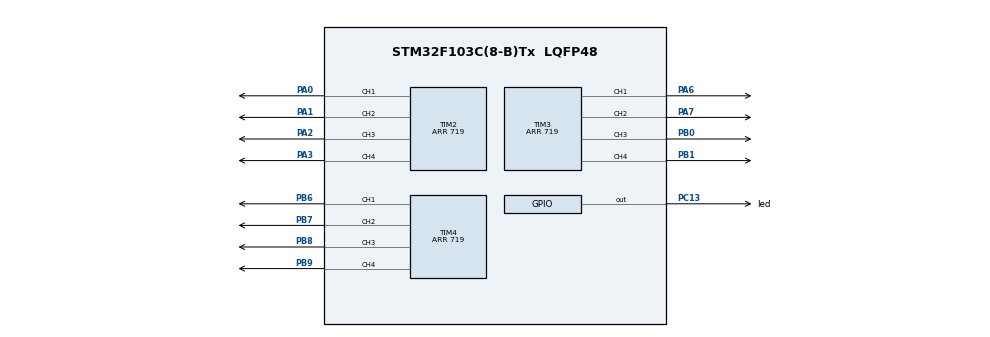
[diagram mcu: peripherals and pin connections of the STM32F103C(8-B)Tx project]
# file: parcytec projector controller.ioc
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Mcu.Family=STM32F1
Mcu.Name=STM32F103C(8-B)Tx
Mcu.Package=LQFP48
NVIC.PriorityGroup=NVIC_PRIORITYGROUP_4
PA0-WKUP.Signal=S_TIM2_CH1_ETR
PA1.Signal=S_TIM2_CH2
PA13.Mode=Serial_Wire
PA13.Signal=SYS_JTMS-SWDIO
PA14.Mode=Serial_Wire
PA14.Signal=SYS_JTCK-SWCLK
PA2.Signal=S_TIM2_CH3
PA3.Signal=S_TIM2_CH4
PA6.Signal=S_TIM3_CH1
PA7.Signal=S_TIM3_CH2
PB0.Signal=S_TIM3_CH3
PB1.Signal=S_TIM3_CH4
PB6.Signal=S_TIM4_CH1
PB7.Signal=S_TIM4_CH2
PB8.Signal=S_TIM4_CH3
PB9.Signal=S_TIM4_CH4
PC13-TAMPER-RTC.GPIO_Label=led
PC13-TAMPER-RTC.Signal=GPIO_Output
PD0-OSC_IN.Mode=HSE-External-Oscillator
PD0-OSC_IN.Signal=RCC_OSC_IN
PD1-OSC_OUT.Mode=HSE-External-Oscillator
PD1-OSC_OUT.Signal=RCC_OSC_OUT
ProjectManager.HeapSize=0x200
ProjectManager.StackSize=0x400
ProjectManager.TargetToolchain=MDK-ARM V5.32
RCC.APB1Freq_Value=8000000
RCC.APB2Freq_Value=8000000
SH.S_TIM2_CH1_ETR.0=TIM2_CH1,PWM Generation1 CH1
SH.S_TIM2_CH2.0=TIM2_CH2,PWM Generation2 CH2
SH.S_TIM2_CH3.0=TIM2_CH3,PWM Generation3 CH3
SH.S_TIM2_CH4.0=TIM2_CH4,PWM Generation4 CH4
SH.S_TIM3_CH1.0=TIM3_CH1,PWM Generation1 CH1
SH.S_TIM3_CH2.0=TIM3_CH2,PWM Generation2 CH2
SH.S_TIM3_CH3.0=TIM3_CH3,PWM Generation3 CH3
SH.S_TIM3_CH4.0=TIM3_CH4,PWM Generation4 CH4
SH.S_TIM4_CH1.0=TIM4_CH1,PWM Generation1 CH1
SH.S_TIM4_CH2.0=TIM4_CH2,PWM Generation2 CH2
SH.S_TIM4_CH3.0=TIM4_CH3,PWM Generation3 CH3
SH.S_TIM4_CH4.0=TIM4_CH4,PWM Generation4 CH4
TIM2.Channel-PWM\ Generation1\ CH1=TIM_CHANNEL_1
TIM2.Channel-PWM\ Generation2\ CH2=TIM_CHANNEL_2
TIM2.Channel-PWM\ Generation3\ CH3=TIM_CHANNEL_3
TIM2.Channel-PWM\ Generation4\ CH4=TIM_CHANNEL_4
TIM2.Period=719
TIM3.Channel-PWM\ Generation1\ CH1=TIM_CHANNEL_1
TIM3.Channel-PWM\ Generation2\ CH2=TIM_CHANNEL_2
TIM3.Channel-PWM\ Generation3\ CH3=TIM_CHANNEL_3
TIM3.Channel-PWM\ Generation4\ CH4=TIM_CHANNEL_4
TIM3.Period=719
TIM4.Channel-PWM\ Generation1\ CH1=TIM_CHANNEL_1
TIM4.Channel-PWM\ Generation2\ CH2=TIM_CHANNEL_2
TIM4.Channel-PWM\ Generation3\ CH3=TIM_CHANNEL_3
TIM4.Channel-PWM\ Generation4\ CH4=TIM_CHANNEL_4
TIM4.Period=719
board=custom

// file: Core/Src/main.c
#include "main.h"

int period_value=72000/100;

TIM_HandleTypeDef htim2;
TIM_HandleTypeDef htim3;
TIM_HandleTypeDef htim4;

void SystemClock_Config(void);
static void MX_GPIO_Init(void);
static void MX_TIM2_Init(void);
static void MX_TIM3_Init(void);
static void MX_TIM4_Init(void);

int main(void)
{
  HAL_Init();
  SystemClock_Config();

  MX_GPIO_Init();
  MX_TIM2_Init();
  MX_TIM3_Init();
  MX_TIM4_Init();

	/////////////////declare variables///////////////////

	int delay_value=1000/10;   // 1000/freq of pwm for led  PC13

///////////////configuration of TIM1/////////////////
	///////0.6 A without any LED//////////

	int compare_value1=period_value*0.45; // defining the duty cycle of pwm/////////////  1  ///////  D C =0.4    1A /// D C =0.38 0.9A   0.3+0.9=1.2 //// 0.5
	int compare_value2=period_value*0.2; // defining the duty cycle of pwm//////////////  2  ///////  D C =0.15   1A /// D C =0.1 0.9A    1.2+0.9=2.1/////0.2
	int compare_value3=period_value*0.3; // defining the duty cycle of pwm/////////////  3  ///////  D C =0.25   1A /// D C =0.22 0.9A   2.1+0.9=3/////0.3
	int compare_value4=period_value*0.2; // defining the duty cycle of pwm/////////////  4  ///////  D C =0.15   1A /// D C =0.11 0.9A		3+0.9=3.9////0.2
	int compare_value5=period_value*0.25; // defining the duty cycle of pwm/////////////  5  ///////  D C =0.15   1A /// D C =0.13 0.9A		3.9+0.9=4.8///0.25
	int compare_value6=period_value*0.45; // defining the duty cycle of pwm/////////////  6  ///////  D C =---    1A /// D C =0.45 0.9A		4.8+0.9=5.7////0.55
	int compare_value7=period_value*0.45; // defining the duty cycle of pwm //
	int compare_value8=period_value*0.45; // defining the duty cycle of pwm //
	int compare_value9=period_value*0; // defining the duty cycle of pwm //
	int compare_value10=period_value*0; // defining the duty cycle of pwm //
	int compare_value11=period_value*0; // defining the duty cycle of pwm //
	int compare_value12=period_value*0.4; // defining the duty cycle of pwm //////////////////////0.4

	// setting the values //
	__HAL_TIM_SET_COMPARE(&htim2,TIM_CHANNEL_1,compare_value1);
	__HAL_TIM_SET_COMPARE(&htim2,TIM_CHANNEL_2,compare_value2);
	__HAL_TIM_SET_COMPARE(&htim2,TIM_CHANNEL_3,compare_value3);
	__HAL_TIM_SET_COMPARE(&htim2,TIM_CHANNEL_4,compare_value4);
	__HAL_TIM_SET_COMPARE(&htim3,TIM_CHANNEL_1,compare_value5);
	__HAL_TIM_SET_COMPARE(&htim3,TIM_CHANNEL_2,compare_value6);
	__HAL_TIM_SET_COMPARE(&htim3,TIM_CHANNEL_3,compare_value7);
	__HAL_TIM_SET_COMPARE(&htim3,TIM_CHANNEL_4,compare_value8);
//	__HAL_TIM_SET_COMPARE(&htim4,TIM_CHANNEL_1,compare_value9);
//	__HAL_TIM_SET_COMPARE(&htim4,TIM_CHANNEL_2,compare_value10);
//	__HAL_TIM_SET_COMPARE(&htim4,TIM_CHANNEL_3,compare_value11);
	__HAL_TIM_SET_COMPARE(&htim4,TIM_CHANNEL_4,compare_value12);

	//starting timers//
	HAL_TIM_PWM_Start(&htim2,TIM_CHANNEL_1);
	HAL_TIM_PWM_Start(&htim2,TIM_CHANNEL_2);
	HAL_TIM_PWM_Start(&htim2,TIM_CHANNEL_3);
	HAL_TIM_PWM_Start(&htim2,TIM_CHANNEL_4);
	HAL_TIM_PWM_Start(&htim3,TIM_CHANNEL_1);
	HAL_TIM_PWM_Start(&htim3,TIM_CHANNEL_2);
	HAL_TIM_PWM_Start(&htim3,TIM_CHANNEL_3);
	HAL_TIM_PWM_Start(&htim3,TIM_CHANNEL_4);
	HAL_TIM_PWM_Start(&htim4,TIM_CHANNEL_1);
	HAL_TIM_PWM_Start(&htim4,TIM_CHANNEL_2);
	HAL_TIM_PWM_Start(&htim4,TIM_CHANNEL_3);
	HAL_TIM_PWM_Start(&htim4,TIM_CHANNEL_4);

  while (1)
  {
		HAL_GPIO_WritePin(led_GPIO_Port,led_Pin,1);
		HAL_Delay(50);
		HAL_GPIO_WritePin(led_GPIO_Port,led_Pin,0);
		HAL_Delay(50);

  }

}

void SystemClock_Config(void)
{
  RCC_OscInitTypeDef RCC_OscInitStruct = {0};
  RCC_ClkInitTypeDef RCC_ClkInitStruct = {0};

  /** Initializes the RCC Oscillators according to the specified parameters
  * in the RCC_OscInitTypeDef structure.
  */
  RCC_OscInitStruct.OscillatorType = RCC_OSCILLATORTYPE_HSE;
  RCC_OscInitStruct.HSEState = RCC_HSE_ON;
  RCC_OscInitStruct.HSEPredivValue = RCC_HSE_PREDIV_DIV1;
  RCC_OscInitStruct.HSIState = RCC_HSI_ON;
  RCC_OscInitStruct.PLL.PLLState = RCC_PLL_ON;
  RCC_OscInitStruct.PLL.PLLSource = RCC_PLLSOURCE_HSE;
  RCC_OscInitStruct.PLL.PLLMUL = RCC_PLL_MUL9;
  if (HAL_RCC_OscConfig(&RCC_OscInitStruct) != HAL_OK)
  {
    Error_Handler();
  }

  /** Initializes the CPU, AHB and APB buses clocks
  */
  RCC_ClkInitStruct.ClockType = RCC_CLOCKTYPE_HCLK|RCC_CLOCKTYPE_SYSCLK
                              |RCC_CLOCKTYPE_PCLK1|RCC_CLOCKTYPE_PCLK2;
  RCC_ClkInitStruct.SYSCLKSource = RCC_SYSCLKSOURCE_PLLCLK;
  RCC_ClkInitStruct.AHBCLKDivider = RCC_SYSCLK_DIV1;
  RCC_ClkInitStruct.APB1CLKDivider = RCC_HCLK_DIV2;
  RCC_ClkInitStruct.APB2CLKDivider = RCC_HCLK_DIV1;

  if (HAL_RCC_ClockConfig(&RCC_ClkInitStruct, FLASH_LATENCY_2) != HAL_OK)
  {
    Error_Handler();
  }
}

static void MX_TIM2_Init(void)
{

  TIM_MasterConfigTypeDef sMasterConfig = {0};
  TIM_OC_InitTypeDef sConfigOC = {0};

  htim2.Instance = TIM2;
  htim2.Init.Prescaler = 0;
  htim2.Init.CounterMode = TIM_COUNTERMODE_UP;
  htim2.Init.Period = 719;
  htim2.Init.ClockDivision = TIM_CLOCKDIVISION_DIV1;
  htim2.Init.AutoReloadPreload = TIM_AUTORELOAD_PRELOAD_DISABLE;
  if (HAL_TIM_PWM_Init(&htim2) != HAL_OK)
  {
    Error_Handler();
  }
  sMasterConfig.MasterOutputTrigger = TIM_TRGO_RESET;
  sMasterConfig.MasterSlaveMode = TIM_MASTERSLAVEMODE_DISABLE;
  if (HAL_TIMEx_MasterConfigSynchronization(&htim2, &sMasterConfig) != HAL_OK)
  {
    Error_Handler();
  }
  sConfigOC.OCMode = TIM_OCMODE_PWM1;
  sConfigOC.Pulse = 0;
  sConfigOC.OCPolarity = TIM_OCPOLARITY_HIGH;
  sConfigOC.OCFastMode = TIM_OCFAST_DISABLE;
  if (HAL_TIM_PWM_ConfigChannel(&htim2, &sConfigOC, TIM_CHANNEL_1) != HAL_OK)
  {
    Error_Handler();
  }
  if (HAL_TIM_PWM_ConfigChannel(&htim2, &sConfigOC, TIM_CHANNEL_2) != HAL_OK)
  {
    Error_Handler();
  }
  if (HAL_TIM_PWM_ConfigChannel(&htim2, &sConfigOC, TIM_CHANNEL_3) != HAL_OK)
  {
    Error_Handler();
  }
  if (HAL_TIM_PWM_ConfigChannel(&htim2, &sConfigOC, TIM_CHANNEL_4) != HAL_OK)
  {
    Error_Handler();
  }
  HAL_TIM_MspPostInit(&htim2);

}

static void MX_TIM3_Init(void)
{

  TIM_MasterConfigTypeDef sMasterConfig = {0};
  TIM_OC_InitTypeDef sConfigOC = {0};

  htim3.Instance = TIM3;
  htim3.Init.Prescaler = 0;
  htim3.Init.CounterMode = TIM_COUNTERMODE_UP;
  htim3.Init.Period = 719;
  htim3.Init.ClockDivision = TIM_CLOCKDIVISION_DIV1;
  htim3.Init.AutoReloadPreload = TIM_AUTORELOAD_PRELOAD_DISABLE;
  if (HAL_TIM_PWM_Init(&htim3) != HAL_OK)
  {
    Error_Handler();
  }
  sMasterConfig.MasterOutputTrigger = TIM_TRGO_RESET;
  sMasterConfig.MasterSlaveMode = TIM_MASTERSLAVEMODE_DISABLE;
  if (HAL_TIMEx_MasterConfigSynchronization(&htim3, &sMasterConfig) != HAL_OK)
  {
    Error_Handler();
  }
  sConfigOC.OCMode = TIM_OCMODE_PWM1;
  sConfigOC.Pulse = 0;
  sConfigOC.OCPolarity = TIM_OCPOLARITY_HIGH;
  sConfigOC.OCFastMode = TIM_OCFAST_DISABLE;
  if (HAL_TIM_PWM_ConfigChannel(&htim3, &sConfigOC, TIM_CHANNEL_1) != HAL_OK)
  {
    Error_Handler();
  }
  if (HAL_TIM_PWM_ConfigChannel(&htim3, &sConfigOC, TIM_CHANNEL_2) != HAL_OK)
  {
    Error_Handler();
  }
  if (HAL_TIM_PWM_ConfigChannel(&htim3, &sConfigOC, TIM_CHANNEL_3) != HAL_OK)
  {
    Error_Handler();
  }
  if (HAL_TIM_PWM_ConfigChannel(&htim3, &sConfigOC, TIM_CHANNEL_4) != HAL_OK)
  {
    Error_Handler();
  }
  HAL_TIM_MspPostInit(&htim3);

}

static void MX_TIM4_Init(void)
{

  TIM_MasterConfigTypeDef sMasterConfig = {0};
  TIM_OC_InitTypeDef sConfigOC = {0};

  htim4.Instance = TIM4;
  htim4.Init.Prescaler = 0;
  htim4.Init.CounterMode = TIM_COUNTERMODE_UP;
  htim4.Init.Period = 719;
  htim4.Init.ClockDivision = TIM_CLOCKDIVISION_DIV1;
  htim4.Init.AutoReloadPreload = TIM_AUTORELOAD_PRELOAD_DISABLE;
  if (HAL_TIM_PWM_Init(&htim4) != HAL_OK)
  {
    Error_Handler();
  }
  sMasterConfig.MasterOutputTrigger = TIM_TRGO_RESET;
  sMasterConfig.MasterSlaveMode = TIM_MASTERSLAVEMODE_DISABLE;
  if (HAL_TIMEx_MasterConfigSynchronization(&htim4, &sMasterConfig) != HAL_OK)
  {
    Error_Handler();
  }
  sConfigOC.OCMode = TIM_OCMODE_PWM1;
  sConfigOC.Pulse = 0;
  sConfigOC.OCPolarity = TIM_OCPOLARITY_HIGH;
  sConfigOC.OCFastMode = TIM_OCFAST_DISABLE;
  if (HAL_TIM_PWM_ConfigChannel(&htim4, &sConfigOC, TIM_CHANNEL_1) != HAL_OK)
  {
    Error_Handler();
  }
  if (HAL_TIM_PWM_ConfigChannel(&htim4, &sConfigOC, TIM_CHANNEL_2) != HAL_OK)
  {
    Error_Handler();
  }
  if (HAL_TIM_PWM_ConfigChannel(&htim4, &sConfigOC, TIM_CHANNEL_3) != HAL_OK)
  {
    Error_Handler();
  }
  if (HAL_TIM_PWM_ConfigChannel(&htim4, &sConfigOC, TIM_CHANNEL_4) != HAL_OK)
  {
    Error_Handler();
  }
  HAL_TIM_MspPostInit(&htim4);

}

static void MX_GPIO_Init(void)
{
  GPIO_InitTypeDef GPIO_InitStruct = {0};

  /* GPIO Ports Clock Enable */
  __HAL_RCC_GPIOC_CLK_ENABLE();
  __HAL_RCC_GPIOD_CLK_ENABLE();
  __HAL_RCC_GPIOA_CLK_ENABLE();
  __HAL_RCC_GPIOB_CLK_ENABLE();

  /*Configure GPIO pin Output Level */
  HAL_GPIO_WritePin(led_GPIO_Port, led_Pin, GPIO_PIN_RESET);

  /*Configure GPIO pin : led_Pin */
  GPIO_InitStruct.Pin = led_Pin;
  GPIO_InitStruct.Mode = GPIO_MODE_OUTPUT_PP;
  GPIO_InitStruct.Pull = GPIO_NOPULL;
  GPIO_InitStruct.Speed = GPIO_SPEED_FREQ_LOW;
  HAL_GPIO_Init(led_GPIO_Port, &GPIO_InitStruct);

}

void Error_Handler(void)
{
  __disable_irq();
  while (1)
  {
  }
}
